VERSION 5.7 ;
  NOWIREEXTENSIONATPIN ON ;
  DIVIDERCHAR "/" ;
  BUSBITCHARS "[]" ;
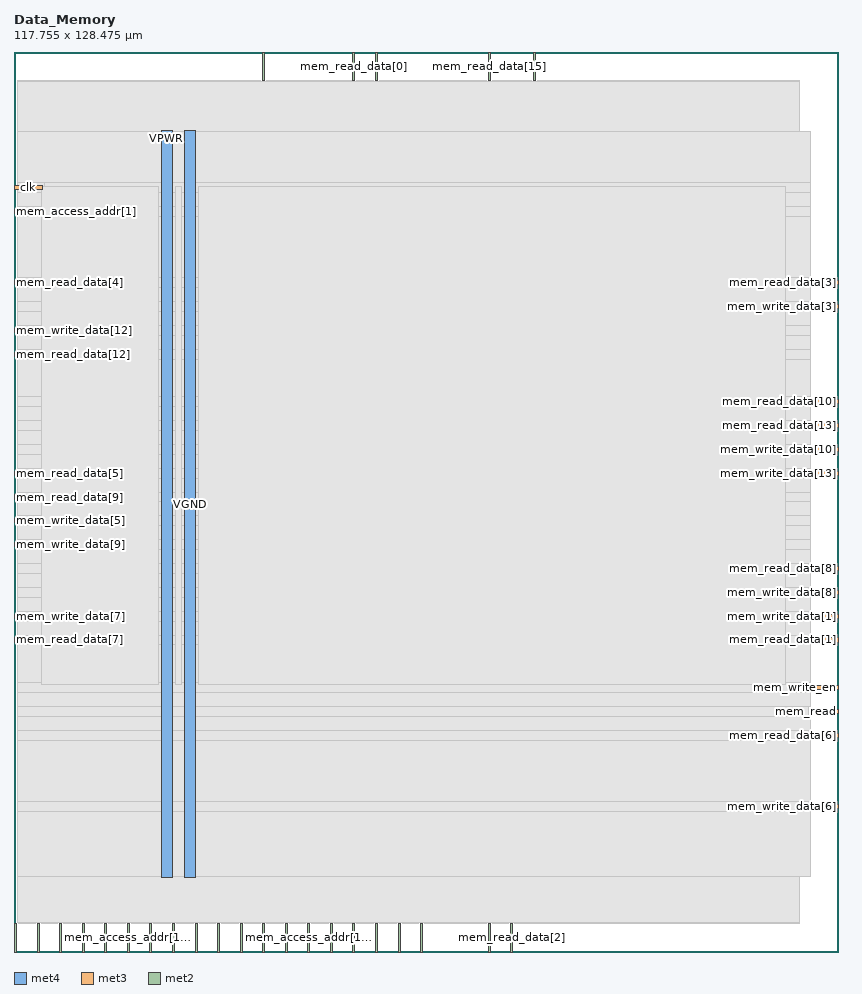
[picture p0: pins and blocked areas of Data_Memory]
MACRO Data_Memory
  CLASS BLOCK ;
  FOREIGN Data_Memory ;
  ORIGIN 0.000 0.000 ;
  SIZE 117.755 BY 128.475 ;
  PIN VGND
    DIRECTION INOUT ;
    USE GROUND ;
    PORT
      LAYER met4 ;
        RECT 24.340 10.640 25.940 117.200 ;
    END
  END VGND
  PIN VPWR
    DIRECTION INOUT ;
    USE POWER ;
    PORT
      LAYER met4 ;
        RECT 21.040 10.640 22.640 117.200 ;
    END
  END VPWR
  PIN clk
    DIRECTION INPUT ;
    USE SIGNAL ;
    ANTENNAGATEAREA 0.852000 ;
    PORT
      LAYER met3 ;
        RECT 0.000 108.840 4.000 109.440 ;
    END
  END clk
  PIN mem_access_addr[0]
    DIRECTION INPUT ;
    USE SIGNAL ;
    PORT
      LAYER met2 ;
        RECT 0.090 0.000 0.370 4.000 ;
    END
  END mem_access_addr[0]
  PIN mem_access_addr[10]
    DIRECTION INPUT ;
    USE SIGNAL ;
    PORT
      LAYER met2 ;
        RECT 3.310 0.000 3.590 4.000 ;
    END
  END mem_access_addr[10]
  PIN mem_access_addr[11]
    DIRECTION INPUT ;
    USE SIGNAL ;
    PORT
      LAYER met2 ;
        RECT 12.970 0.000 13.250 4.000 ;
    END
  END mem_access_addr[11]
  PIN mem_access_addr[12]
    DIRECTION INPUT ;
    USE SIGNAL ;
    PORT
      LAYER met2 ;
        RECT 9.750 0.000 10.030 4.000 ;
    END
  END mem_access_addr[12]
  PIN mem_access_addr[13]
    DIRECTION INPUT ;
    USE SIGNAL ;
    PORT
      LAYER met2 ;
        RECT 25.850 0.000 26.130 4.000 ;
    END
  END mem_access_addr[13]
  PIN mem_access_addr[14]
    DIRECTION INPUT ;
    USE SIGNAL ;
    PORT
      LAYER met2 ;
        RECT 41.950 0.000 42.230 4.000 ;
    END
  END mem_access_addr[14]
  PIN mem_access_addr[15]
    DIRECTION INPUT ;
    USE SIGNAL ;
    PORT
      LAYER met2 ;
        RECT 16.190 0.000 16.470 4.000 ;
    END
  END mem_access_addr[15]
  PIN mem_access_addr[1]
    DIRECTION INPUT ;
    USE SIGNAL ;
    ANTENNAGATEAREA 0.196500 ;
    PORT
      LAYER met3 ;
        RECT 0.000 105.440 4.000 106.040 ;
    END
  END mem_access_addr[1]
  PIN mem_access_addr[2]
    DIRECTION INPUT ;
    USE SIGNAL ;
    ANTENNAGATEAREA 0.196500 ;
    PORT
      LAYER met2 ;
        RECT 51.610 0.000 51.890 4.000 ;
    END
  END mem_access_addr[2]
  PIN mem_access_addr[3]
    DIRECTION INPUT ;
    USE SIGNAL ;
    ANTENNAGATEAREA 0.196500 ;
    PORT
      LAYER met2 ;
        RECT 54.830 0.000 55.110 4.000 ;
    END
  END mem_access_addr[3]
  PIN mem_access_addr[4]
    DIRECTION INPUT ;
    USE SIGNAL ;
    PORT
      LAYER met2 ;
        RECT 22.630 0.000 22.910 4.000 ;
    END
  END mem_access_addr[4]
  PIN mem_access_addr[5]
    DIRECTION INPUT ;
    USE SIGNAL ;
    PORT
      LAYER met2 ;
        RECT 58.050 0.000 58.330 4.000 ;
    END
  END mem_access_addr[5]
  PIN mem_access_addr[6]
    DIRECTION INPUT ;
    USE SIGNAL ;
    PORT
      LAYER met2 ;
        RECT 6.530 0.000 6.810 4.000 ;
    END
  END mem_access_addr[6]
  PIN mem_access_addr[7]
    DIRECTION INPUT ;
    USE SIGNAL ;
    PORT
      LAYER met2 ;
        RECT 32.290 0.000 32.570 4.000 ;
    END
  END mem_access_addr[7]
  PIN mem_access_addr[8]
    DIRECTION INPUT ;
    USE SIGNAL ;
    PORT
      LAYER met2 ;
        RECT 35.510 0.000 35.790 4.000 ;
    END
  END mem_access_addr[8]
  PIN mem_access_addr[9]
    DIRECTION INPUT ;
    USE SIGNAL ;
    PORT
      LAYER met2 ;
        RECT 38.730 0.000 39.010 4.000 ;
    END
  END mem_access_addr[9]
  PIN mem_read
    DIRECTION INPUT ;
    USE SIGNAL ;
    ANTENNAGATEAREA 0.196500 ;
    PORT
      LAYER met3 ;
        RECT 113.755 34.040 117.755 34.640 ;
    END
  END mem_read
  PIN mem_read_data[0]
    DIRECTION OUTPUT ;
    USE SIGNAL ;
    ANTENNADIFFAREA 0.445500 ;
    PORT
      LAYER met2 ;
        RECT 48.390 124.475 48.670 128.475 ;
    END
  END mem_read_data[0]
  PIN mem_read_data[10]
    DIRECTION OUTPUT ;
    USE SIGNAL ;
    ANTENNADIFFAREA 0.445500 ;
    PORT
      LAYER met3 ;
        RECT 113.755 78.240 117.755 78.840 ;
    END
  END mem_read_data[10]
  PIN mem_read_data[11]
    DIRECTION OUTPUT ;
    USE SIGNAL ;
    ANTENNADIFFAREA 0.445500 ;
    PORT
      LAYER met2 ;
        RECT 48.390 0.000 48.670 4.000 ;
    END
  END mem_read_data[11]
  PIN mem_read_data[12]
    DIRECTION OUTPUT ;
    USE SIGNAL ;
    ANTENNADIFFAREA 0.445500 ;
    PORT
      LAYER met3 ;
        RECT 0.000 85.040 4.000 85.640 ;
    END
  END mem_read_data[12]
  PIN mem_read_data[13]
    DIRECTION OUTPUT ;
    USE SIGNAL ;
    ANTENNADIFFAREA 0.445500 ;
    PORT
      LAYER met3 ;
        RECT 113.755 74.840 117.755 75.440 ;
    END
  END mem_read_data[13]
  PIN mem_read_data[14]
    DIRECTION OUTPUT ;
    USE SIGNAL ;
    ANTENNADIFFAREA 0.445500 ;
    PORT
      LAYER met2 ;
        RECT 29.070 0.000 29.350 4.000 ;
    END
  END mem_read_data[14]
  PIN mem_read_data[15]
    DIRECTION OUTPUT ;
    USE SIGNAL ;
    ANTENNADIFFAREA 0.445500 ;
    PORT
      LAYER met2 ;
        RECT 67.710 124.475 67.990 128.475 ;
    END
  END mem_read_data[15]
  PIN mem_read_data[1]
    DIRECTION OUTPUT ;
    USE SIGNAL ;
    ANTENNADIFFAREA 0.445500 ;
    PORT
      LAYER met3 ;
        RECT 113.755 44.240 117.755 44.840 ;
    END
  END mem_read_data[1]
  PIN mem_read_data[2]
    DIRECTION OUTPUT ;
    USE SIGNAL ;
    ANTENNADIFFAREA 0.445500 ;
    PORT
      LAYER met2 ;
        RECT 70.930 0.000 71.210 4.000 ;
    END
  END mem_read_data[2]
  PIN mem_read_data[3]
    DIRECTION OUTPUT ;
    USE SIGNAL ;
    ANTENNADIFFAREA 0.445500 ;
    PORT
      LAYER met3 ;
        RECT 113.755 95.240 117.755 95.840 ;
    END
  END mem_read_data[3]
  PIN mem_read_data[4]
    DIRECTION OUTPUT ;
    USE SIGNAL ;
    ANTENNADIFFAREA 0.445500 ;
    PORT
      LAYER met3 ;
        RECT 0.000 95.240 4.000 95.840 ;
    END
  END mem_read_data[4]
  PIN mem_read_data[5]
    DIRECTION OUTPUT ;
    USE SIGNAL ;
    ANTENNADIFFAREA 0.445500 ;
    PORT
      LAYER met3 ;
        RECT 0.000 68.040 4.000 68.640 ;
    END
  END mem_read_data[5]
  PIN mem_read_data[6]
    DIRECTION OUTPUT ;
    USE SIGNAL ;
    ANTENNADIFFAREA 0.445500 ;
    PORT
      LAYER met3 ;
        RECT 113.755 30.640 117.755 31.240 ;
    END
  END mem_read_data[6]
  PIN mem_read_data[7]
    DIRECTION OUTPUT ;
    USE SIGNAL ;
    ANTENNADIFFAREA 0.445500 ;
    PORT
      LAYER met3 ;
        RECT 0.000 44.240 4.000 44.840 ;
    END
  END mem_read_data[7]
  PIN mem_read_data[8]
    DIRECTION OUTPUT ;
    USE SIGNAL ;
    ANTENNADIFFAREA 0.445500 ;
    PORT
      LAYER met3 ;
        RECT 113.755 54.440 117.755 55.040 ;
    END
  END mem_read_data[8]
  PIN mem_read_data[9]
    DIRECTION OUTPUT ;
    USE SIGNAL ;
    ANTENNADIFFAREA 0.445500 ;
    PORT
      LAYER met3 ;
        RECT 0.000 64.640 4.000 65.240 ;
    END
  END mem_read_data[9]
  PIN mem_write_data[0]
    DIRECTION INPUT ;
    USE SIGNAL ;
    ANTENNAGATEAREA 0.213000 ;
    PORT
      LAYER met2 ;
        RECT 51.610 124.475 51.890 128.475 ;
    END
  END mem_write_data[0]
  PIN mem_write_data[10]
    DIRECTION INPUT ;
    USE SIGNAL ;
    ANTENNAGATEAREA 0.213000 ;
    PORT
      LAYER met3 ;
        RECT 113.755 71.440 117.755 72.040 ;
    END
  END mem_write_data[10]
  PIN mem_write_data[11]
    DIRECTION INPUT ;
    USE SIGNAL ;
    ANTENNAGATEAREA 0.213000 ;
    PORT
      LAYER met2 ;
        RECT 45.170 0.000 45.450 4.000 ;
    END
  END mem_write_data[11]
  PIN mem_write_data[12]
    DIRECTION INPUT ;
    USE SIGNAL ;
    ANTENNAGATEAREA 0.213000 ;
    PORT
      LAYER met3 ;
        RECT 0.000 88.440 4.000 89.040 ;
    END
  END mem_write_data[12]
  PIN mem_write_data[13]
    DIRECTION INPUT ;
    USE SIGNAL ;
    ANTENNAGATEAREA 0.213000 ;
    PORT
      LAYER met3 ;
        RECT 113.755 68.040 117.755 68.640 ;
    END
  END mem_write_data[13]
  PIN mem_write_data[14]
    DIRECTION INPUT ;
    USE SIGNAL ;
    ANTENNAGATEAREA 0.213000 ;
    PORT
      LAYER met2 ;
        RECT 19.410 0.000 19.690 4.000 ;
    END
  END mem_write_data[14]
  PIN mem_write_data[15]
    DIRECTION INPUT ;
    USE SIGNAL ;
    ANTENNAGATEAREA 0.213000 ;
    PORT
      LAYER met2 ;
        RECT 74.150 124.475 74.430 128.475 ;
    END
  END mem_write_data[15]
  PIN mem_write_data[1]
    DIRECTION INPUT ;
    USE SIGNAL ;
    ANTENNAGATEAREA 0.213000 ;
    PORT
      LAYER met3 ;
        RECT 113.755 47.640 117.755 48.240 ;
    END
  END mem_write_data[1]
  PIN mem_write_data[2]
    DIRECTION INPUT ;
    USE SIGNAL ;
    ANTENNAGATEAREA 0.213000 ;
    PORT
      LAYER met2 ;
        RECT 67.710 0.000 67.990 4.000 ;
    END
  END mem_write_data[2]
  PIN mem_write_data[3]
    DIRECTION INPUT ;
    USE SIGNAL ;
    ANTENNAGATEAREA 0.213000 ;
    PORT
      LAYER met3 ;
        RECT 113.755 91.840 117.755 92.440 ;
    END
  END mem_write_data[3]
  PIN mem_write_data[4]
    DIRECTION INPUT ;
    USE SIGNAL ;
    ANTENNAGATEAREA 0.213000 ;
    PORT
      LAYER met2 ;
        RECT 35.510 124.475 35.790 128.475 ;
    END
  END mem_write_data[4]
  PIN mem_write_data[5]
    DIRECTION INPUT ;
    USE SIGNAL ;
    ANTENNAGATEAREA 0.213000 ;
    PORT
      LAYER met3 ;
        RECT 0.000 61.240 4.000 61.840 ;
    END
  END mem_write_data[5]
  PIN mem_write_data[6]
    DIRECTION INPUT ;
    USE SIGNAL ;
    ANTENNAGATEAREA 0.213000 ;
    PORT
      LAYER met3 ;
        RECT 113.755 20.440 117.755 21.040 ;
    END
  END mem_write_data[6]
  PIN mem_write_data[7]
    DIRECTION INPUT ;
    USE SIGNAL ;
    ANTENNAGATEAREA 0.213000 ;
    PORT
      LAYER met3 ;
        RECT 0.000 47.640 4.000 48.240 ;
    END
  END mem_write_data[7]
  PIN mem_write_data[8]
    DIRECTION INPUT ;
    USE SIGNAL ;
    ANTENNAGATEAREA 0.213000 ;
    PORT
      LAYER met3 ;
        RECT 113.755 51.040 117.755 51.640 ;
    END
  END mem_write_data[8]
  PIN mem_write_data[9]
    DIRECTION INPUT ;
    USE SIGNAL ;
    ANTENNAGATEAREA 0.213000 ;
    PORT
      LAYER met3 ;
        RECT 0.000 57.840 4.000 58.440 ;
    END
  END mem_write_data[9]
  PIN mem_write_en
    DIRECTION INPUT ;
    USE SIGNAL ;
    ANTENNAGATEAREA 0.196500 ;
    PORT
      LAYER met3 ;
        RECT 113.755 37.440 117.755 38.040 ;
    END
  END mem_write_en
  OBS
      LAYER nwell ;
        RECT 5.330 10.795 111.970 117.150 ;
      LAYER li1 ;
        RECT 5.520 10.795 111.780 117.045 ;
      LAYER met1 ;
        RECT 4.210 10.640 112.170 117.200 ;
      LAYER met2 ;
        RECT 0.550 124.195 35.230 124.475 ;
        RECT 36.070 124.195 48.110 124.475 ;
        RECT 48.950 124.195 51.330 124.475 ;
        RECT 52.170 124.195 67.430 124.475 ;
        RECT 68.270 124.195 73.870 124.475 ;
        RECT 74.710 124.195 112.150 124.475 ;
        RECT 0.550 4.280 112.150 124.195 ;
        RECT 0.650 4.000 3.030 4.280 ;
        RECT 3.870 4.000 6.250 4.280 ;
        RECT 7.090 4.000 9.470 4.280 ;
        RECT 10.310 4.000 12.690 4.280 ;
        RECT 13.530 4.000 15.910 4.280 ;
        RECT 16.750 4.000 19.130 4.280 ;
        RECT 19.970 4.000 22.350 4.280 ;
        RECT 23.190 4.000 25.570 4.280 ;
        RECT 26.410 4.000 28.790 4.280 ;
        RECT 29.630 4.000 32.010 4.280 ;
        RECT 32.850 4.000 35.230 4.280 ;
        RECT 36.070 4.000 38.450 4.280 ;
        RECT 39.290 4.000 41.670 4.280 ;
        RECT 42.510 4.000 44.890 4.280 ;
        RECT 45.730 4.000 48.110 4.280 ;
        RECT 48.950 4.000 51.330 4.280 ;
        RECT 52.170 4.000 54.550 4.280 ;
        RECT 55.390 4.000 57.770 4.280 ;
        RECT 58.610 4.000 67.430 4.280 ;
        RECT 68.270 4.000 70.650 4.280 ;
        RECT 71.490 4.000 112.150 4.280 ;
      LAYER met3 ;
        RECT 0.525 109.840 113.755 117.125 ;
        RECT 4.400 108.440 113.755 109.840 ;
        RECT 0.525 106.440 113.755 108.440 ;
        RECT 4.400 105.040 113.755 106.440 ;
        RECT 0.525 96.240 113.755 105.040 ;
        RECT 4.400 94.840 113.355 96.240 ;
        RECT 0.525 92.840 113.755 94.840 ;
        RECT 0.525 91.440 113.355 92.840 ;
        RECT 0.525 89.440 113.755 91.440 ;
        RECT 4.400 88.040 113.755 89.440 ;
        RECT 0.525 86.040 113.755 88.040 ;
        RECT 4.400 84.640 113.755 86.040 ;
        RECT 0.525 79.240 113.755 84.640 ;
        RECT 0.525 77.840 113.355 79.240 ;
        RECT 0.525 75.840 113.755 77.840 ;
        RECT 0.525 74.440 113.355 75.840 ;
        RECT 0.525 72.440 113.755 74.440 ;
        RECT 0.525 71.040 113.355 72.440 ;
        RECT 0.525 69.040 113.755 71.040 ;
        RECT 4.400 67.640 113.355 69.040 ;
        RECT 0.525 65.640 113.755 67.640 ;
        RECT 4.400 64.240 113.755 65.640 ;
        RECT 0.525 62.240 113.755 64.240 ;
        RECT 4.400 60.840 113.755 62.240 ;
        RECT 0.525 58.840 113.755 60.840 ;
        RECT 4.400 57.440 113.755 58.840 ;
        RECT 0.525 55.440 113.755 57.440 ;
        RECT 0.525 54.040 113.355 55.440 ;
        RECT 0.525 52.040 113.755 54.040 ;
        RECT 0.525 50.640 113.355 52.040 ;
        RECT 0.525 48.640 113.755 50.640 ;
        RECT 4.400 47.240 113.355 48.640 ;
        RECT 0.525 45.240 113.755 47.240 ;
        RECT 4.400 43.840 113.355 45.240 ;
        RECT 0.525 38.440 113.755 43.840 ;
        RECT 0.525 37.040 113.355 38.440 ;
        RECT 0.525 35.040 113.755 37.040 ;
        RECT 0.525 33.640 113.355 35.040 ;
        RECT 0.525 31.640 113.755 33.640 ;
        RECT 0.525 30.240 113.355 31.640 ;
        RECT 0.525 21.440 113.755 30.240 ;
        RECT 0.525 20.040 113.355 21.440 ;
        RECT 0.525 10.715 113.755 20.040 ;
      LAYER met4 ;
        RECT 3.975 38.255 20.640 109.305 ;
        RECT 23.040 38.255 23.940 109.305 ;
        RECT 26.340 38.255 110.105 109.305 ;
  END
END Data_Memory
END LIBRARY

